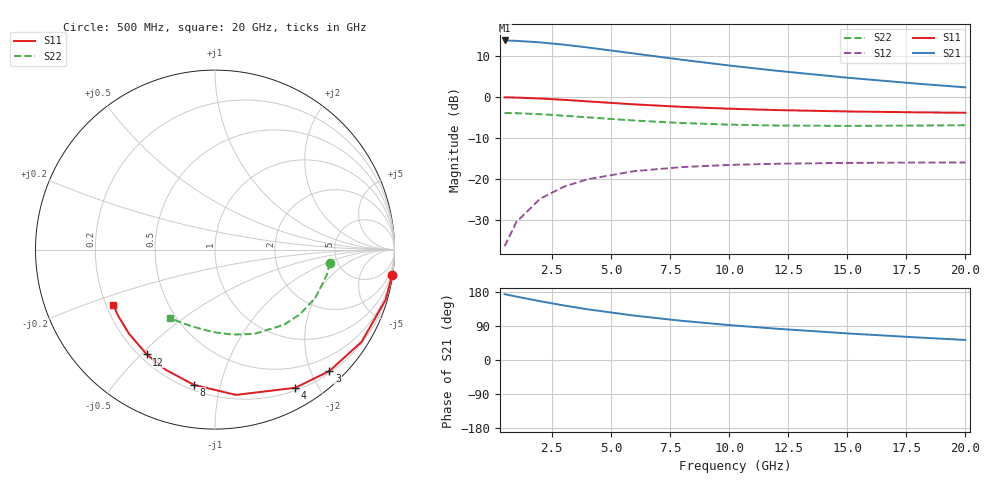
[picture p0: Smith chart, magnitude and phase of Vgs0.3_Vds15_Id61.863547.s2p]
# Hz S RI R 50
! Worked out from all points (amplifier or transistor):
!   12 points, 500 MHz to 20 GHz, reference 50 ohm
!   highest |S21| = 13.9 dB at 500 MHz (marker M1)
!   |S21| within 3 dB of that: start of sweep to 5.724 GHz
!   unconditionally stable (mu >= 1): nowhere
!   at 2 GHz: K = 0.09, MSG = 19.1 dB, |S12| = -24.9 dB
!   at 8 GHz: K = 0.38, MSG = 13.1 dB, |S12| = -17.1 dB
!   at 20 GHz: K = 0.97, MSG = 9.2 dB, |S12| = -16.0 dB
!   S11 on the Smith chart (normalised r, x): 500 MHz: 0, -14; 3 GHz: 0.23, -2.30; 4 GHz: 0.23, -1.71; 8 GHz: 0.23, -0.83; 12 GHz: 0.23, -0.52; 20 GHz: 0.23, -0.24
5e8  0.9873 -0.1432  -4.916 0.5498  0.00146 0.015  0.6388 -0.0739
1e9  0.9502 -0.2799  -4.772 1.074  0.0057 0.0293  0.6215 -0.1449
2e9  0.8171 -0.5135  -4.255 1.967  0.0209 0.0532  0.559 -0.2686
3e9  0.6375 -0.6764  -3.558 2.584  0.0414 0.069  0.4742 -0.3598
4e9  0.4473 -0.7698  -2.822 2.929  0.063 0.0766  0.3834 -0.4191
6e9  0.1165 -0.8095  -1.551 3.047  0.0999 0.0751  0.2212 -0.4692
8e9  -0.1181 -0.7535  -0.666 2.796  0.1251 0.0628  0.0986 -0.4736
1e10  -0.2748 -0.6695  -0.0932 2.443  0.1408 0.0476  0.00817 -0.4622
1.2e10  -0.3801 -0.5838  0.2725 2.092  0.1501 0.0328  -0.0617 -0.4468
1.5e10  -0.48 -0.4677  0.588 1.631  0.1569 0.0128  -0.1441 -0.4225
1.8e10  -0.5398 -0.3687  0.744 1.259  0.1588 -0.00406  -0.2111 -0.3975
2e10  -0.5662 -0.3106  0.797 1.054  0.1585 -0.0138  -0.2503 -0.38
